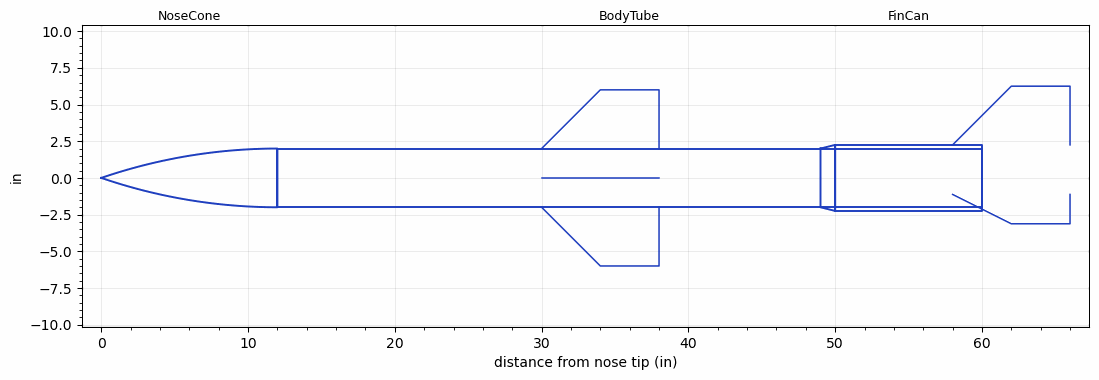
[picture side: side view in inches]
<RASAeroDocument>
 <FileVersion>2</FileVersion>
 <RocketDesign>
  <NoseCone>
   <Length>12.0</Length>
   <Diameter>4.0</Diameter>
   <Shape>Tangent Ogive</Shape>
   <Location>0</Location>
  </NoseCone>
  <BodyTube>
   <Length>48.0</Length>
   <Diameter>4.0</Diameter>
   <Location>12.0</Location>
   <Fin>
    <Count>4</Count>
    <Chord>8.0</Chord>
    <Span>4.0</Span>
    <SweepDistance>4.0</SweepDistance>
    <TipChord>4.0</TipChord>
    <Thickness>0.125</Thickness>
    <Location>30.0</Location>
    <AirfoilSection>Hexagonal</AirfoilSection>
    <FX1>2.0</FX1>
    <FX3>2.0</FX3>
   </Fin>
  </BodyTube>
  <FinCan>
   <Length>10.0</Length>
   <Diameter>4.5</Diameter>
   <InsideDiameter>4.0</InsideDiameter>
   <Location>60.0</Location>
   <ShoulderLength>1.0</ShoulderLength>
   <Offset>-10.0</Offset>
   <Fin>
    <Count>3</Count>
    <Chord>8.0</Chord>
    <Span>4.0</Span>
    <SweepDistance>4.0</SweepDistance>
    <TipChord>4.0</TipChord>
    <Thickness>0.125</Thickness>
    <Location>2.0</Location>
    <AirfoilSection>Square</AirfoilSection>
    <FX1>2.0</FX1>
    <FX3>2.0</FX3>
   </Fin>
  </FinCan>
  <Surface>Smooth (Zero Roughness)</Surface>
  <ModifiedBarrowman>False</ModifiedBarrowman>
  <Turbulence>False</Turbulence>
  <UseBooster1>False</UseBooster1>
  <UseBooster2>False</UseBooster2>
  <Comments>Oracle case: combo_two_fin_sets</Comments>
 </RocketDesign>
 <LaunchSite>
  <Altitude>0</Altitude>
  <Pressure>0</Pressure>
  <RodAngle>0</RodAngle>
  <RodLength>10</RodLength>
  <Temperature>59</Temperature>
  <WindSpeed>0</WindSpeed>
 </LaunchSite>
 <Recovery>
  <Altitude1>1000</Altitude1>
  <DeviceType1>None</DeviceType1>
  <Event1>False</Event1>
  <Size1>1</Size1>
  <EventType1>None</EventType1>
  <CD1>1.33</CD1>
  <Altitude2>1000</Altitude2>
  <DeviceType2>None</DeviceType2>
  <Event2>False</Event2>
  <Size2>1</Size2>
  <EventType2>None</EventType2>
  <CD2>1.33</CD2>
 </Recovery>
</RASAeroDocument>
